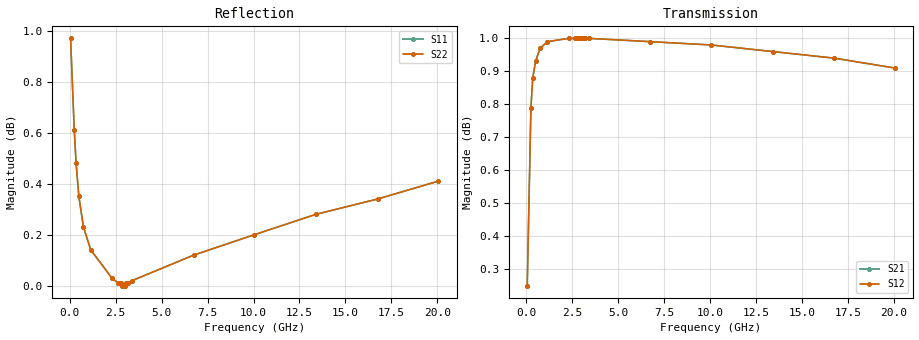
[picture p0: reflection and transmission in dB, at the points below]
! AVX Thin Film Operation		Date: may 2004
! Description: Accu-P® Series, Thin Film, SMD, RF Capacitor
! Part Number: 0201ZK8R2BBW
! 50 MHz  -  10.05 GHz
! Serial Measurements
# mhz S db R 50
!	S11		S21		S12		S22
!	dB	Phase	dB	Phase	dB	Phase	dB	Phase
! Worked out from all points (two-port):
!   401 points, 50 MHz to 20.05 GHz, reference 50 ohm
!   highest |S21| = 1.00 dB at 2.3 GHz (marker M1); lowest = 0.3 dB at 50 MHz (marker M2)
!   |S21| within 3 dB of the highest: start of sweep to end of sweep
!   lowest |S11| = 0.0 dB at 2.95 GHz (marker M3)
!   |S11| at or under -10 dB: nowhere
!   |S22| runs from 0.0 to 1.0 dB; largest |S21 - S12| = 0
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50  0.97 -14.4  0.25 75.5  0.25 75.5  0.97 -14.4
250  0.61 -52.3  0.79 37.6  0.79 37.6  0.61 -52.3
350  0.48 -61.2  0.88 28.6  0.88 28.6  0.48 -61.2
500  0.35 -69.1  0.93 20.6  0.93 20.6  0.35 -69.1
750  0.23 -76.1  0.97 13.6  0.97 13.6  0.23 -76.1
1150  0.14 -81.3  0.99 8.1  0.99 8.1  0.14 -81.3
2300  0.03 -85.4  1.00 1.9  1.00 1.9  0.03 -85.4
2650  0.01 -82.6  1.00 0.8  1.00 0.8  0.01 -82.6
2750  0.01 -79.0  1.00 0.5  1.00 0.5  0.01 -79.0
2800  0.01 -75.1  1.00 0.3  1.00 0.3  0.01 -75.1
2850  0.00 -66.7  1.00 0.2  1.00 0.2  0.00 -66.7
2950  0.00 31.0  1.00 -0.1  1.00 -0.1  0.00 31.0
3000  0.00 63.7  1.00 -0.2  1.00 -0.2  0.00 63.7
3050  0.01 73.5  1.00 -0.3  1.00 -0.3  0.01 73.5
3100  0.01 77.9  1.00 -0.4  1.00 -0.4  0.01 77.9
3200  0.01 81.8  1.00 -0.7  1.00 -0.7  0.01 81.8
3400  0.02 84.4  1.00 -1.1  1.00 -1.1  0.02 84.4
6750  0.12 82.2  0.99 -7.1  0.99 -7.1  0.12 82.2
10050  0.20 77.8  0.98 -11.7  0.98 -11.7  0.20 77.8
13400  0.28 73.6  0.96 -16.1  0.96 -16.1  0.28 73.6
16750  0.34 69.6  0.94 -20.1  0.94 -20.1  0.34 69.6
20050  0.41 65.9  0.91 -23.9  0.91 -23.9  0.41 65.9
